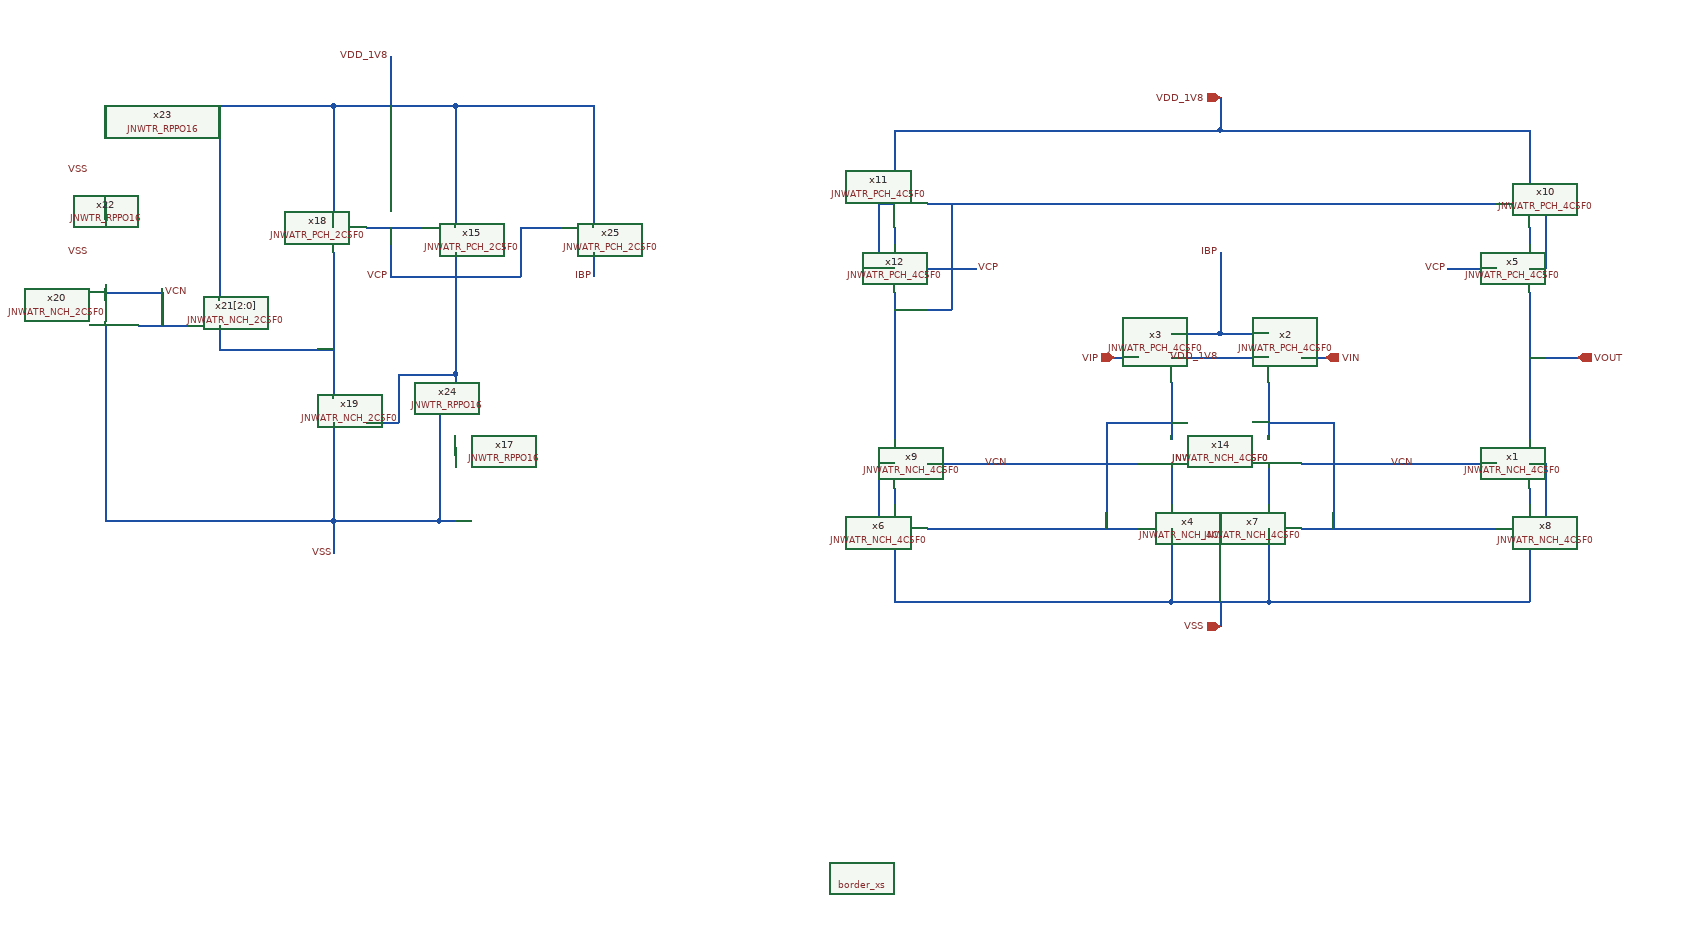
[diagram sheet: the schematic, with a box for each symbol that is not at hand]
v {xschem version=3.4.7 file_version=1.2}
G {}
K {}
V {}
S {}
E {}
P 4 1 20 30 {}
P 4 1 -120 -290 {}
N 310 -640 340 -640 {lab=VIP}
N 540 -640 570 -640 {lab=VIN}
N 40 -400 40 -360 {lab=VSS}
N 380 -400 380 -360 {lab=VSS}
N 380 -340 500 -340 {lab=VSS}
N 500 -400 500 -360 {lab=VSS}
N 820 -400 820 -360 {lab=VSS}
N 440 -340 440 -310 {lab=VSS}
N 380 -670 440 -670 {lab=IBP}
N 440 -670 500 -670 {lab=IBP}
N 820 -880 820 -860 {lab=VDD_1V8}
N 40 -880 40 -860 {lab=VDD_1V8}
N 440 -960 440 -920 {lab=VDD_1V8}
N 820 -860 820 -830 {lab=VDD_1V8}
N 40 -860 40 -830 {lab=VDD_1V8}
N 500 -430 500 -400 {lab=VSS}
N 820 -430 820 -400 {lab=VSS}
N 40 -430 40 -400 {lab=VSS}
N 380 -430 380 -400 {lab=VSS}
N 820 -920 820 -880 {lab=VDD_1V8}
N 40 -920 40 -880 {lab=VDD_1V8}
N 820 -360 820 -340 {lab=VSS}
N 500 -360 500 -340 {lab=VSS}
N 380 -360 380 -340 {lab=VSS}
N 40 -360 40 -340 {lab=VSS}
N 440 -690 440 -670 {lab=IBP}
N -610 -800 -540 -800 {lab=VCP}
N -650 -950 -500 -950 {lab=VDD_1V8}
N -580 -1010 -580 -950 {lab=VDD_1V8}
N -500 -770 -500 -710 {lab=VCP}
N -580 -740 -500 -740 {lab=VCP}
N -580 -800 -580 -740 {lab=VCP}
N -650 -770 -650 -590 {lab=#net1}
N -500 -650 -500 -620 {lab=VCP}
N -570 -620 -500 -620 {lab=VCP}
N -570 -620 -570 -560 {lab=VCP}
N -610 -560 -570 -560 {lab=VCP}
N -500 -530 -500 -520 {lab=#net2}
N -500 -620 -500 -610 {lab=VCP}
N -520 -480 -520 -440 {lab=VSS}
N -520 -440 -500 -440 {lab=VSS}
N -650 -530 -650 -440 {lab=VSS}
N -650 -440 -520 -440 {lab=VSS}
N -500 -830 -500 -800 {lab=VDD_1V8}
N -650 -830 -650 -800 {lab=VDD_1V8}
N -930 -830 -930 -810 {lab=#net3}
N -930 -950 -650 -950 {lab=VDD_1V8}
N -930 -730 -930 -710 {lab=VCN}
N -930 -720 -860 -720 {lab=VCN}
N -860 -720 -860 -680 {lab=VCN}
N -890 -680 -830 -680 {lab=VCN}
N -930 -650 -930 -440 {lab=VSS}
N -930 -440 -650 -440 {lab=VSS}
N -930 -680 -930 -650 {lab=VSS}
N -790 -680 -790 -650 {lab=#net1}
N -790 -650 -650 -650 {lab=#net1}
N -790 -830 -790 -710 {lab=VDD_1V8}
N -650 -560 -650 -530 {lab=VSS}
N -650 -440 -650 -400 {lab=VSS}
N -930 -950 -930 -910 {lab=VDD_1V8}
N -790 -950 -790 -830 {lab=VDD_1V8}
N -650 -950 -650 -830 {lab=VDD_1V8}
N -500 -950 -500 -830 {lab=VDD_1V8}
N -520 -570 -520 -480 {lab=VSS}
N -500 -950 -330 -950 {lab=VDD_1V8}
N -330 -950 -330 -830 {lab=VDD_1V8}
N -330 -830 -330 -800 {lab=VDD_1V8}
N -330 -770 -330 -740 {lab=IBP}
N -380 -800 -370 -800 {lab=VCP}
N -500 -740 -420 -740 {lab=VCP}
N -420 -800 -420 -740 {lab=VCP}
N -420 -800 -380 -800 {lab=VCP}
N 40 -800 40 -780 {lab=#net4}
N 40 -720 40 -540 {lab=#net5}
N 40 -480 40 -460 {lab=#net6}
N 820 -480 820 -460 {lab=#net7}
N 820 -720 820 -540 {lab=VOUT}
N 820 -800 820 -780 {lab=#net8}
N 440 -770 440 -690 {lab=IBP}
N 500 -480 500 -460 {lab=#net9}
N 380 -480 380 -460 {lab=#net10}
N 80 -430 340 -430 {lab=#net11}
N 80 -510 340 -510 {lab=VCN}
N 540 -510 780 -510 {lab=VCN}
N 540 -430 780 -430 {lab=#net12}
N 500 -610 500 -540 {lab=#net12}
N 380 -610 380 -540 {lab=#net11}
N 40 -340 380 -340 {lab=VSS}
N 500 -340 820 -340 {lab=VSS}
N 580 -560 580 -430 {lab=#net12}
N 500 -560 580 -560 {lab=#net12}
N 300 -560 300 -430 {lab=#net11}
N 300 -560 380 -560 {lab=#net11}
N 720 -830 780 -830 {lab=#net5}
N 80 -830 720 -830 {lab=#net5}
N 110 -830 110 -700 {lab=#net5}
N 40 -700 110 -700 {lab=#net5}
N 80 -750 140 -750 {lab=VCP}
N 720 -750 780 -750 {lab=VCP}
N 440 -920 820 -920 {lab=VDD_1V8}
N 40 -920 440 -920 {lab=VDD_1V8}
N 820 -640 880 -640 {lab=VOUT}
N 380 -510 380 -480 {lab=#net10}
N 500 -510 500 -480 {lab=#net9}
N 20 -750 40 -750 {lab=VDD_1V8}
N 20 -830 20 -750 {lab=VDD_1V8}
N 20 -830 40 -830 {lab=VDD_1V8}
N 20 -510 40 -510 {lab=VSS}
N 20 -510 20 -430 {lab=VSS}
N 20 -430 40 -430 {lab=VSS}
N 820 -750 840 -750 {lab=VDD_1V8}
N 840 -830 840 -750 {lab=VDD_1V8}
N 820 -830 840 -830 {lab=VDD_1V8}
N 820 -510 840 -510 {lab=VSS}
N 840 -510 840 -430 {lab=VSS}
N 820 -430 840 -430 {lab=VSS}
N 380 -640 500 -640 {lab=VDD_1V8}
N -500 -710 -500 -650 {lab=VCP}
C {cborder/border_xs.sym} 0 0 0 0 {
user="walterbr"
company="Walter"}
C {devices/ipin.sym} 440 -960 0 0 {name=p1 lab=VDD_1V8}
C {devices/ipin.sym} 310 -640 0 0 {name=p4 lab=VIP}
C {devices/ipin.sym} 570 -640 0 1 {name=p5 lab=VIN}
C {devices/ipin.sym} 440 -310 0 0 {name=p2 lab=VSS}
C {JNW_ATR_SKY130A/JNWATR_PCH_4C5F0.sym} 540 -640 0 1 {name=x2}
C {JNW_ATR_SKY130A/JNWATR_PCH_4C5F0.sym} 340 -640 0 0 {name=x3}
C {JNW_ATR_SKY130A/JNWATR_NCH_4C5F0.sym} 340 -430 0 0 {name=x4}
C {JNW_ATR_SKY130A/JNWATR_NCH_4C5F0.sym} 80 -430 0 1 {name=x6 }
C {JNW_ATR_SKY130A/JNWATR_NCH_4C5F0.sym} 540 -430 0 1 {name=x7}
C {JNW_ATR_SKY130A/JNWATR_NCH_4C5F0.sym} 780 -430 0 0 {name=x8 }
C {JNW_ATR_SKY130A/JNWATR_PCH_4C5F0.sym} 80 -830 0 1 {name=x11}
C {JNW_ATR_SKY130A/JNWATR_PCH_4C5F0.sym} 780 -830 0 0 {name=x10}
C {JNW_ATR_SKY130A/JNWATR_PCH_2C5F0.sym} -540 -800 0 0 {name=x15 }
C {JNW_TR_SKY130A/JNWTR_RPPO16.sym} -500 -520 1 0 {name=x17 }
C {JNW_ATR_SKY130A/JNWATR_PCH_2C5F0.sym} -610 -800 0 1 {name=x18 }
C {JNW_ATR_SKY130A/JNWATR_NCH_2C5F0.sym} -610 -560 0 1 {name=x19 }
C {JNW_ATR_SKY130A/JNWATR_NCH_2C5F0.sym} -890 -680 0 1 {name=x20 }
C {JNW_ATR_SKY130A/JNWATR_NCH_2C5F0.sym} -830 -680 0 0 {name=x21[2:0] }
C {JNW_TR_SKY130A/JNWTR_RPPO16.sym} -930 -810 1 0 {name=x22 }
C {devices/lab_wire.sym} -950 -770 0 0 {name=p16 sig_type=std_logic lab=VSS}
C {JNW_TR_SKY130A/JNWTR_RPPO16.sym} -930 -910 1 0 {name=x23 }
C {devices/lab_wire.sym} -950 -870 0 0 {name=p12 sig_type=std_logic lab=VSS}
C {JNW_TR_SKY130A/JNWTR_RPPO16.sym} -500 -610 1 0 {name=x24 }
C {JNW_ATR_SKY130A/JNWATR_PCH_2C5F0.sym} -370 -800 0 0 {name=x25}
C {devices/lab_pin.sym} -580 -1010 0 0 {name=p10 sig_type=std_logic lab=VDD_1V8}
C {devices/lab_pin.sym} -650 -400 0 0 {name=p11 sig_type=std_logic lab=VSS}
C {devices/lab_pin.sym} -860 -720 0 1 {name=p14 sig_type=std_logic lab=VCN}
C {devices/lab_pin.sym} -580 -740 0 0 {name=p15 sig_type=std_logic lab=VCP}
C {JNW_ATR_SKY130A/JNWATR_NCH_4C5F0.sym} 780 -510 0 0 {name=x1 }
C {JNW_ATR_SKY130A/JNWATR_PCH_4C5F0.sym} 780 -750 0 0 {name=x5}
C {JNW_ATR_SKY130A/JNWATR_NCH_4C5F0.sym} 80 -510 0 1 {name=x9 }
C {JNW_ATR_SKY130A/JNWATR_PCH_4C5F0.sym} 80 -750 0 1 {name=x12}
C {devices/lab_pin.sym} -330 -740 0 0 {name=p3 sig_type=std_logic lab=IBP}
C {devices/lab_pin.sym} 440 -770 0 0 {name=p6 sig_type=std_logic lab=IBP}
C {JNW_ATR_SKY130A/JNWATR_NCH_4C5F0.sym} 340 -510 0 0 {name=x13}
C {JNW_ATR_SKY130A/JNWATR_NCH_4C5F0.sym} 540 -510 0 1 {name=x14}
C {devices/lab_pin.sym} 180 -510 1 1 {name=p7 sig_type=std_logic lab=VCN}
C {devices/lab_pin.sym} 680 -510 1 1 {name=p8 sig_type=std_logic lab=VCN}
C {devices/lab_pin.sym} 140 -750 0 1 {name=p9 sig_type=std_logic lab=VCP}
C {devices/lab_pin.sym} 720 -750 0 0 {name=p13 sig_type=std_logic lab=VCP}
C {devices/opin.sym} 880 -640 0 0 {name=p17 lab=VOUT}
C {devices/lab_pin.sym} 440 -640 3 0 {name=p18 sig_type=std_logic lab=VDD_1V8}
